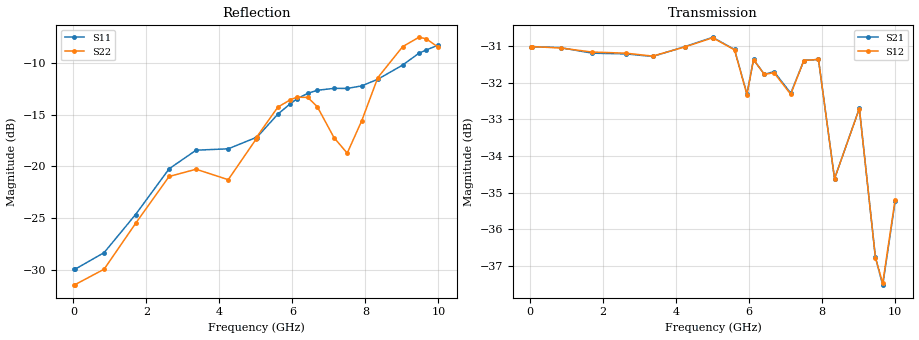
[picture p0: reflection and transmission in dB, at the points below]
! Integrated Device Technology
! Corporate Headquarters
! 6024 Silver Creek Valley Road
! San Jose, CA 95138  USA
! Phone:  1-408-284-8200
! Toll Free:  1-800-223-1366
! Webpage:  http://www.idt.com/
! Timing and RF Division
! 515 Groton Road, Suite 102
! Westford, MA 01886-6024
! Device:  F1958
! Description: 7-bit 0.25 dB Digital Step Attenuator
! Frequency:  0.001 -  6.000 GHz
! Package:  4x4 mm Thin QFN Plastic Package: 24 pin
! Ports:  2 RF, 12 DC
!  Pin  1  = D0
!  Pin  2  = VDD
!  Pin  3  = VMODE
!  Pin  4  = GND
!  Pin  5  = RF1  =  Port 1
!  Pin  6  = GND
!  Pin  7  = GND
!  Pin  8  = GND
!  Pin  9  = GND
!  Pin 10  = GND
!  Pin 11  = GND
!  Pin 12  = GND
!  Pin 13  = GND
!  Pin 14  = RF2  =  Port 2
!  Pin 15  = GND
!  Pin 16  = LE
!  Pin 17  = CLK
!  Pin 18  = DATA
!  Pin 19  = D6
!  Pin 20  = D5
!  Pin 21  = D4
!  Pin 22  = D3
!  Pin 23  = D2
!  Pin 24  = D1
! State:  121
! Atten State:  30.25 dB
! Voltage:  +3.30 Volts
! Current:  0.258 mA
! Data:  The device was measured on a F1958 evaluation board which has
!  individual transmission lines to the RF pins.  Data was collected
!  using a calibrated network analyzer.  The evaluation board was
!  de-embedded using Automatic Fixture Removal (AFR).
!  The reference plane is the edge of the package pin.
! Misc:
!  Action Tracker AT0419
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# GHz S dB R 50
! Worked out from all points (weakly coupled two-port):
!   500 points, 20 MHz to 10 GHz, reference 50 ohm
!   highest |S21| = -30.77 dB at 5 GHz (marker M1); lowest = -37.5 dB at 9.66 GHz (marker M2)
!   lowest |S11| = -29.9 dB at 40 MHz (marker M3), VSWR 1.07, Z = 46.9 - j0.0454 ohm
!   |S11| at or under -10 dB: start of sweep to 9.052 GHz
!   |S22| runs from -31.7 to -7.4 dB; largest |S21 - S12| = 0.00029
!   S11 on the Smith chart (normalised r, x): 20 MHz: 0.94, -0.00; 6.42 GHz: 0.66, +0.17; 10 GHz: 0.67, +0.60
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0.02  -29.90 -178.9  -31.04 -0.1  -31.04 -0.1  -31.46 -179.0
0.04  -29.93 -179.1  -31.02 -0.3  -31.02 -0.3  -31.42 -178.5
0.84  -28.32 171.7  -31.05 -9.3  -31.06 -9.3  -29.92 172.7
1.7  -24.65 171.8  -31.20 -18.5  -31.17 -18.5  -25.51 171.4
2.62  -20.23 177.5  -31.22 -28.3  -31.20 -28.3  -20.97 -179.8
3.36  -18.43 -175.5  -31.29 -36.5  -31.28 -36.8  -20.27 -170.0
4.24  -18.30 -179.0  -31.02 -45.7  -31.03 -45.9  -21.28 168.4
5  -17.21 161.8  -30.77 -55.2  -30.78 -55.3  -17.38 137.2
5.02  -17.21 161.0  -30.78 -55.7  -30.79 -55.7  -17.16 138.2
5.6  -14.95 150.9  -31.10 -64.3  -31.11 -64.2  -14.27 139.9
5.94  -13.95 148.4  -32.31 -67.6  -32.33 -67.7  -13.57 148.2
6.12  -13.48 148.7  -31.37 -68.0  -31.38 -68.0  -13.31 151.1
6.42  -12.94 147.6  -31.78 -72.8  -31.78 -72.7  -13.34 156.5
6.68  -12.65 146.6  -31.70 -75.2  -31.73 -75.1  -14.23 156.9
7.14  -12.46 142.6  -32.29 -80.0  -32.32 -79.9  -17.23 150.7
7.5  -12.47 138.0  -31.40 -83.5  -31.40 -83.4  -18.72 119.0
7.9  -12.22 128.7  -31.37 -99.5  -31.37 -99.5  -15.57 89.2
8.34  -11.58 118.7  -34.62 -104.7  -34.62 -104.9  -11.42 84.0
9.02  -10.21 107.5  -32.70 -105.3  -32.71 -105.4  -8.43 97.7
9.46  -9.08 102.2  -36.76 -110.8  -36.77 -111.0  -7.54 106.8
9.66  -8.77 100.4  -37.52 -97.2  -37.47 -97.2  -7.66 110.0
10  -8.27 99.4  -35.24 -83.6  -35.19 -83.7  -8.51 113.6
